VERSION 5.7 ;
  NOWIREEXTENSIONATPIN ON ;
  DIVIDERCHAR "/" ;
  BUSBITCHARS "[]" ;
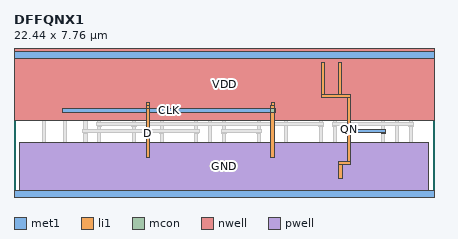
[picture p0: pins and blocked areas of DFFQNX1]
MACRO DFFQNX1
  CLASS CORE ;
  FOREIGN DFFQNX1 ;
  ORIGIN 0.000 0.000 ;
  SIZE 22.440 BY 7.760 ;
  SYMMETRY X Y ;
  SITE unitrh ;
  PIN QN
    DIRECTION OUTPUT ;
    USE SIGNAL ;
    ANTENNAGATEAREA 1.033250 ;
    ANTENNADIFFAREA 1.351900 ;
    PORT
      LAYER met1 ;
        RECT 17.765 3.595 17.995 3.625 ;
        RECT 19.615 3.595 19.845 3.625 ;
        RECT 17.735 3.425 19.875 3.595 ;
        RECT 17.765 3.395 17.995 3.425 ;
        RECT 19.615 3.395 19.845 3.425 ;
    END
    PORT
      LAYER li1 ;
        RECT 16.435 5.465 16.605 7.200 ;
        RECT 17.315 5.465 17.485 7.200 ;
        RECT 16.435 5.295 17.965 5.465 ;
        RECT 17.795 1.920 17.965 5.295 ;
        RECT 17.355 1.750 17.965 1.920 ;
        RECT 17.355 1.015 17.525 1.750 ;
      LAYER mcon ;
        RECT 17.795 3.425 17.965 3.595 ;
    END
  END QN
  PIN D
    DIRECTION INPUT ;
    USE SIGNAL ;
    ANTENNAGATEAREA 1.027250 ;
    PORT
      LAYER li1 ;
        RECT 7.095 4.890 7.265 5.045 ;
        RECT 7.065 4.715 7.265 4.890 ;
        RECT 7.065 2.095 7.235 4.715 ;
    END
  END D
  PIN CLK
    DIRECTION INPUT ;
    USE SIGNAL ;
    ANTENNAGATEAREA 2.042100 ;
    PORT
      LAYER met1 ;
        RECT 2.595 4.705 2.825 4.735 ;
        RECT 13.695 4.705 13.925 4.735 ;
        RECT 2.565 4.535 13.955 4.705 ;
        RECT 2.595 4.505 2.825 4.535 ;
        RECT 13.695 4.505 13.925 4.535 ;
    END
    PORT
      LAYER li1 ;
        RECT 13.755 4.890 13.925 5.045 ;
        RECT 13.725 4.715 13.925 4.890 ;
        RECT 13.725 2.095 13.895 4.715 ;
      LAYER mcon ;
        RECT 13.725 4.535 13.895 4.705 ;
    END
  END CLK
  PIN VDD
    DIRECTION INOUT ;
    USE POWER ;
    SHAPE ABUTMENT ;
    PORT
      LAYER nwell ;
        RECT 0.000 4.110 22.440 7.940 ;
      LAYER met1 ;
        RECT 0.000 7.410 22.440 7.760 ;
    END
  END VDD
  PIN GND
    DIRECTION INOUT ;
    USE GROUND ;
    SHAPE ABUTMENT ;
    PORT
      LAYER pwell ;
        RECT 0.320 0.350 22.120 2.900 ;
        RECT 0.000 0.000 22.440 0.350 ;
      LAYER met1 ;
        RECT 0.000 0.000 22.440 0.350 ;
    END
  END GND
  OBS
      LAYER li1 ;
        RECT 0.000 7.410 22.440 7.760 ;
        RECT 0.320 4.290 0.660 7.410 ;
        RECT 1.495 5.395 1.665 7.410 ;
        RECT 1.935 5.420 2.105 7.200 ;
        RECT 2.375 5.735 2.545 7.410 ;
        RECT 2.815 5.420 2.985 7.200 ;
        RECT 3.255 5.735 3.425 7.410 ;
        RECT 3.695 5.420 3.865 7.200 ;
        RECT 4.135 5.735 4.305 7.410 ;
        RECT 1.935 5.250 4.645 5.420 ;
        RECT 0.320 0.350 0.660 2.900 ;
        RECT 1.515 2.095 1.685 5.045 ;
        RECT 2.625 2.095 2.795 5.045 ;
        RECT 3.735 2.095 3.905 5.045 ;
        RECT 0.995 1.855 1.165 1.935 ;
        RECT 1.965 1.855 2.135 1.935 ;
        RECT 2.935 1.855 3.105 1.935 ;
        RECT 0.995 1.685 3.105 1.855 ;
        RECT 0.995 0.555 1.165 1.685 ;
        RECT 1.480 0.350 1.650 1.310 ;
        RECT 1.965 0.805 2.135 1.685 ;
        RECT 2.935 1.605 3.105 1.685 ;
        RECT 2.455 1.260 2.625 1.340 ;
        RECT 3.505 1.260 3.675 1.935 ;
        RECT 4.475 1.930 4.645 5.250 ;
        RECT 5.130 4.290 5.470 7.410 ;
        RECT 6.005 5.315 6.175 7.410 ;
        RECT 6.445 5.465 6.615 7.200 ;
        RECT 6.885 5.735 7.055 7.410 ;
        RECT 7.325 5.465 7.495 7.200 ;
        RECT 7.765 5.735 7.935 7.410 ;
        RECT 6.445 5.295 7.975 5.465 ;
        RECT 2.455 1.090 3.675 1.260 ;
        RECT 2.455 1.010 2.625 1.090 ;
        RECT 2.935 0.805 3.105 0.885 ;
        RECT 1.965 0.635 3.105 0.805 ;
        RECT 1.965 0.555 2.135 0.635 ;
        RECT 2.935 0.555 3.105 0.635 ;
        RECT 3.505 0.805 3.675 1.090 ;
        RECT 3.990 1.760 4.645 1.930 ;
        RECT 3.990 1.025 4.160 1.760 ;
        RECT 4.475 0.805 4.645 1.575 ;
        RECT 3.505 0.635 4.645 0.805 ;
        RECT 3.505 0.555 3.675 0.635 ;
        RECT 4.475 0.555 4.645 0.635 ;
        RECT 5.130 0.350 5.470 2.900 ;
        RECT 6.325 2.095 6.495 5.045 ;
        RECT 5.910 1.845 6.080 1.925 ;
        RECT 6.880 1.845 7.050 1.925 ;
        RECT 7.805 1.920 7.975 5.295 ;
        RECT 8.460 4.290 8.800 7.410 ;
        RECT 9.335 5.315 9.505 7.410 ;
        RECT 9.775 5.465 9.945 7.200 ;
        RECT 10.215 5.735 10.385 7.410 ;
        RECT 10.655 5.465 10.825 7.200 ;
        RECT 11.095 5.735 11.265 7.410 ;
        RECT 9.775 5.295 11.305 5.465 ;
        RECT 5.910 1.675 7.050 1.845 ;
        RECT 5.910 0.545 6.080 1.675 ;
        RECT 6.395 0.350 6.565 1.300 ;
        RECT 6.880 0.795 7.050 1.675 ;
        RECT 7.365 1.750 7.975 1.920 ;
        RECT 7.365 1.015 7.535 1.750 ;
        RECT 7.850 0.795 8.020 1.565 ;
        RECT 6.880 0.625 8.020 0.795 ;
        RECT 6.880 0.545 7.050 0.625 ;
        RECT 7.850 0.545 8.020 0.625 ;
        RECT 8.460 0.350 8.800 2.900 ;
        RECT 9.655 2.095 9.825 5.045 ;
        RECT 10.425 4.890 10.595 5.045 ;
        RECT 10.395 4.715 10.595 4.890 ;
        RECT 10.395 2.095 10.565 4.715 ;
        RECT 9.240 1.845 9.410 1.925 ;
        RECT 10.210 1.845 10.380 1.925 ;
        RECT 11.135 1.920 11.305 5.295 ;
        RECT 11.790 4.290 12.130 7.410 ;
        RECT 12.665 5.315 12.835 7.410 ;
        RECT 13.105 5.465 13.275 7.200 ;
        RECT 13.545 5.735 13.715 7.410 ;
        RECT 13.985 5.465 14.155 7.200 ;
        RECT 14.425 5.735 14.595 7.410 ;
        RECT 13.105 5.295 14.635 5.465 ;
        RECT 9.240 1.675 10.380 1.845 ;
        RECT 9.240 0.545 9.410 1.675 ;
        RECT 9.725 0.350 9.895 1.300 ;
        RECT 10.210 0.795 10.380 1.675 ;
        RECT 10.695 1.750 11.305 1.920 ;
        RECT 10.695 1.015 10.865 1.750 ;
        RECT 11.180 0.795 11.350 1.565 ;
        RECT 10.210 0.625 11.350 0.795 ;
        RECT 10.210 0.545 10.380 0.625 ;
        RECT 11.180 0.545 11.350 0.625 ;
        RECT 11.790 0.350 12.130 2.900 ;
        RECT 12.985 2.095 13.155 5.045 ;
        RECT 12.570 1.845 12.740 1.925 ;
        RECT 13.540 1.845 13.710 1.925 ;
        RECT 14.465 1.920 14.635 5.295 ;
        RECT 15.120 4.290 15.460 7.410 ;
        RECT 15.995 5.315 16.165 7.410 ;
        RECT 16.875 5.735 17.045 7.410 ;
        RECT 17.755 5.735 17.925 7.410 ;
        RECT 12.570 1.675 13.710 1.845 ;
        RECT 12.570 0.545 12.740 1.675 ;
        RECT 13.055 0.350 13.225 1.300 ;
        RECT 13.540 0.795 13.710 1.675 ;
        RECT 14.025 1.750 14.635 1.920 ;
        RECT 14.025 1.015 14.195 1.750 ;
        RECT 14.510 0.795 14.680 1.565 ;
        RECT 13.540 0.625 14.680 0.795 ;
        RECT 13.540 0.545 13.710 0.625 ;
        RECT 14.510 0.545 14.680 0.625 ;
        RECT 15.120 0.350 15.460 2.900 ;
        RECT 16.315 2.095 16.485 5.045 ;
        RECT 17.085 4.890 17.255 5.045 ;
        RECT 17.055 4.715 17.255 4.890 ;
        RECT 17.055 2.095 17.225 4.715 ;
        RECT 18.450 4.290 18.790 7.410 ;
        RECT 19.325 5.315 19.495 7.410 ;
        RECT 19.765 5.465 19.935 7.200 ;
        RECT 20.205 5.735 20.375 7.410 ;
        RECT 20.645 5.465 20.815 7.200 ;
        RECT 21.085 5.735 21.255 7.410 ;
        RECT 19.765 5.295 21.295 5.465 ;
        RECT 15.900 1.845 16.070 1.925 ;
        RECT 16.870 1.845 17.040 1.925 ;
        RECT 15.900 1.675 17.040 1.845 ;
        RECT 15.900 0.545 16.070 1.675 ;
        RECT 16.385 0.350 16.555 1.300 ;
        RECT 16.870 0.795 17.040 1.675 ;
        RECT 17.840 0.795 18.010 1.565 ;
        RECT 16.870 0.625 18.010 0.795 ;
        RECT 16.870 0.545 17.040 0.625 ;
        RECT 17.840 0.545 18.010 0.625 ;
        RECT 18.450 0.350 18.790 2.900 ;
        RECT 19.645 2.095 19.815 5.045 ;
        RECT 20.415 4.890 20.585 5.045 ;
        RECT 20.385 4.715 20.585 4.890 ;
        RECT 20.385 2.095 20.555 4.715 ;
        RECT 19.230 1.845 19.400 1.925 ;
        RECT 20.200 1.845 20.370 1.925 ;
        RECT 21.125 1.920 21.295 5.295 ;
        RECT 21.780 4.290 22.120 7.410 ;
        RECT 19.230 1.675 20.370 1.845 ;
        RECT 19.230 0.545 19.400 1.675 ;
        RECT 19.715 0.350 19.885 1.300 ;
        RECT 20.200 0.795 20.370 1.675 ;
        RECT 20.685 1.750 21.295 1.920 ;
        RECT 20.685 1.015 20.855 1.750 ;
        RECT 21.170 0.795 21.340 1.565 ;
        RECT 20.200 0.625 21.340 0.795 ;
        RECT 20.200 0.545 20.370 0.625 ;
        RECT 21.170 0.545 21.340 0.625 ;
        RECT 21.780 0.350 22.120 2.900 ;
        RECT 0.000 0.000 22.440 0.350 ;
      LAYER mcon ;
        RECT 0.775 7.495 0.945 7.665 ;
        RECT 1.145 7.495 1.315 7.665 ;
        RECT 1.515 7.495 1.685 7.665 ;
        RECT 1.885 7.495 2.055 7.665 ;
        RECT 2.255 7.495 2.425 7.665 ;
        RECT 2.625 7.495 2.795 7.665 ;
        RECT 2.995 7.495 3.165 7.665 ;
        RECT 3.365 7.495 3.535 7.665 ;
        RECT 3.735 7.495 3.905 7.665 ;
        RECT 4.105 7.495 4.275 7.665 ;
        RECT 4.475 7.495 4.645 7.665 ;
        RECT 4.845 7.495 5.015 7.665 ;
        RECT 5.585 7.495 5.755 7.665 ;
        RECT 5.955 7.495 6.125 7.665 ;
        RECT 6.325 7.495 6.495 7.665 ;
        RECT 6.695 7.495 6.865 7.665 ;
        RECT 7.065 7.495 7.235 7.665 ;
        RECT 7.435 7.495 7.605 7.665 ;
        RECT 7.805 7.495 7.975 7.665 ;
        RECT 8.175 7.495 8.345 7.665 ;
        RECT 8.915 7.495 9.085 7.665 ;
        RECT 9.285 7.495 9.455 7.665 ;
        RECT 9.655 7.495 9.825 7.665 ;
        RECT 10.025 7.495 10.195 7.665 ;
        RECT 10.395 7.495 10.565 7.665 ;
        RECT 10.765 7.495 10.935 7.665 ;
        RECT 11.135 7.495 11.305 7.665 ;
        RECT 11.505 7.495 11.675 7.665 ;
        RECT 12.245 7.495 12.415 7.665 ;
        RECT 12.615 7.495 12.785 7.665 ;
        RECT 12.985 7.495 13.155 7.665 ;
        RECT 13.355 7.495 13.525 7.665 ;
        RECT 13.725 7.495 13.895 7.665 ;
        RECT 14.095 7.495 14.265 7.665 ;
        RECT 14.465 7.495 14.635 7.665 ;
        RECT 14.835 7.495 15.005 7.665 ;
        RECT 15.575 7.495 15.745 7.665 ;
        RECT 15.945 7.495 16.115 7.665 ;
        RECT 16.315 7.495 16.485 7.665 ;
        RECT 16.685 7.495 16.855 7.665 ;
        RECT 17.055 7.495 17.225 7.665 ;
        RECT 17.425 7.495 17.595 7.665 ;
        RECT 17.795 7.495 17.965 7.665 ;
        RECT 18.165 7.495 18.335 7.665 ;
        RECT 18.905 7.495 19.075 7.665 ;
        RECT 19.275 7.495 19.445 7.665 ;
        RECT 19.645 7.495 19.815 7.665 ;
        RECT 20.015 7.495 20.185 7.665 ;
        RECT 20.385 7.495 20.555 7.665 ;
        RECT 20.755 7.495 20.925 7.665 ;
        RECT 21.125 7.495 21.295 7.665 ;
        RECT 21.495 7.495 21.665 7.665 ;
        RECT 1.515 4.165 1.685 4.335 ;
        RECT 2.625 4.535 2.795 4.705 ;
        RECT 3.735 3.425 3.905 3.595 ;
        RECT 4.475 3.795 4.645 3.965 ;
        RECT 6.325 3.795 6.495 3.965 ;
        RECT 7.805 3.425 7.975 3.595 ;
        RECT 9.655 3.425 9.825 3.595 ;
        RECT 10.395 4.165 10.565 4.335 ;
        RECT 11.135 3.425 11.305 3.595 ;
        RECT 12.985 3.425 13.155 3.595 ;
        RECT 14.465 4.165 14.635 4.335 ;
        RECT 16.315 3.795 16.485 3.965 ;
        RECT 17.055 3.795 17.225 3.965 ;
        RECT 19.645 3.425 19.815 3.595 ;
        RECT 20.385 4.165 20.555 4.335 ;
        RECT 21.125 3.795 21.295 3.965 ;
        RECT 0.775 0.095 0.945 0.265 ;
        RECT 1.145 0.095 1.315 0.265 ;
        RECT 1.515 0.095 1.685 0.265 ;
        RECT 1.885 0.095 2.055 0.265 ;
        RECT 2.255 0.095 2.425 0.265 ;
        RECT 2.625 0.095 2.795 0.265 ;
        RECT 2.995 0.095 3.165 0.265 ;
        RECT 3.365 0.095 3.535 0.265 ;
        RECT 3.735 0.095 3.905 0.265 ;
        RECT 4.105 0.095 4.275 0.265 ;
        RECT 4.475 0.095 4.645 0.265 ;
        RECT 4.845 0.095 5.015 0.265 ;
        RECT 5.585 0.095 5.755 0.265 ;
        RECT 5.955 0.095 6.125 0.265 ;
        RECT 6.325 0.095 6.495 0.265 ;
        RECT 6.695 0.095 6.865 0.265 ;
        RECT 7.065 0.095 7.235 0.265 ;
        RECT 7.435 0.095 7.605 0.265 ;
        RECT 7.805 0.095 7.975 0.265 ;
        RECT 8.175 0.095 8.345 0.265 ;
        RECT 8.915 0.095 9.085 0.265 ;
        RECT 9.285 0.095 9.455 0.265 ;
        RECT 9.655 0.095 9.825 0.265 ;
        RECT 10.025 0.095 10.195 0.265 ;
        RECT 10.395 0.095 10.565 0.265 ;
        RECT 10.765 0.095 10.935 0.265 ;
        RECT 11.135 0.095 11.305 0.265 ;
        RECT 11.505 0.095 11.675 0.265 ;
        RECT 12.245 0.095 12.415 0.265 ;
        RECT 12.615 0.095 12.785 0.265 ;
        RECT 12.985 0.095 13.155 0.265 ;
        RECT 13.355 0.095 13.525 0.265 ;
        RECT 13.725 0.095 13.895 0.265 ;
        RECT 14.095 0.095 14.265 0.265 ;
        RECT 14.465 0.095 14.635 0.265 ;
        RECT 14.835 0.095 15.005 0.265 ;
        RECT 15.575 0.095 15.745 0.265 ;
        RECT 15.945 0.095 16.115 0.265 ;
        RECT 16.315 0.095 16.485 0.265 ;
        RECT 16.685 0.095 16.855 0.265 ;
        RECT 17.055 0.095 17.225 0.265 ;
        RECT 17.425 0.095 17.595 0.265 ;
        RECT 17.795 0.095 17.965 0.265 ;
        RECT 18.165 0.095 18.335 0.265 ;
        RECT 18.905 0.095 19.075 0.265 ;
        RECT 19.275 0.095 19.445 0.265 ;
        RECT 19.645 0.095 19.815 0.265 ;
        RECT 20.015 0.095 20.185 0.265 ;
        RECT 20.385 0.095 20.555 0.265 ;
        RECT 20.755 0.095 20.925 0.265 ;
        RECT 21.125 0.095 21.295 0.265 ;
        RECT 21.495 0.095 21.665 0.265 ;
      LAYER met1 ;
        RECT 1.485 4.335 1.715 4.365 ;
        RECT 10.365 4.335 10.595 4.365 ;
        RECT 14.435 4.335 14.665 4.365 ;
        RECT 20.355 4.335 20.585 4.365 ;
        RECT 1.455 4.165 20.615 4.335 ;
        RECT 1.485 4.135 1.715 4.165 ;
        RECT 10.365 4.135 10.595 4.165 ;
        RECT 14.435 4.135 14.665 4.165 ;
        RECT 20.355 4.135 20.585 4.165 ;
        RECT 4.445 3.965 4.675 3.995 ;
        RECT 6.295 3.965 6.525 3.995 ;
        RECT 16.285 3.965 16.515 3.995 ;
        RECT 17.025 3.965 17.255 3.995 ;
        RECT 21.095 3.965 21.325 3.995 ;
        RECT 4.415 3.795 16.545 3.965 ;
        RECT 16.995 3.795 21.355 3.965 ;
        RECT 4.445 3.765 4.675 3.795 ;
        RECT 6.295 3.765 6.525 3.795 ;
        RECT 16.285 3.765 16.515 3.795 ;
        RECT 17.025 3.765 17.255 3.795 ;
        RECT 21.095 3.765 21.325 3.795 ;
        RECT 3.705 3.595 3.935 3.625 ;
        RECT 7.775 3.595 8.005 3.625 ;
        RECT 9.625 3.595 9.855 3.625 ;
        RECT 11.105 3.595 11.335 3.625 ;
        RECT 12.955 3.595 13.185 3.625 ;
        RECT 3.675 3.425 9.885 3.595 ;
        RECT 11.075 3.425 13.215 3.595 ;
        RECT 3.705 3.395 3.935 3.425 ;
        RECT 7.775 3.395 8.005 3.425 ;
        RECT 9.625 3.395 9.855 3.425 ;
        RECT 11.105 3.395 11.335 3.425 ;
        RECT 12.955 3.395 13.185 3.425 ;
  END
END DFFQNX1
END LIBRARY

